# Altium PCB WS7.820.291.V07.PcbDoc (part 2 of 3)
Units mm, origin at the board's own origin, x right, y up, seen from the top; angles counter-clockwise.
Board outline 240.26 x 41.75 mm, 4 copper layers (Top Layer, S2, S3, Bottom Layer); 262 components, 157 nets, 756 pads, 1428 vias.

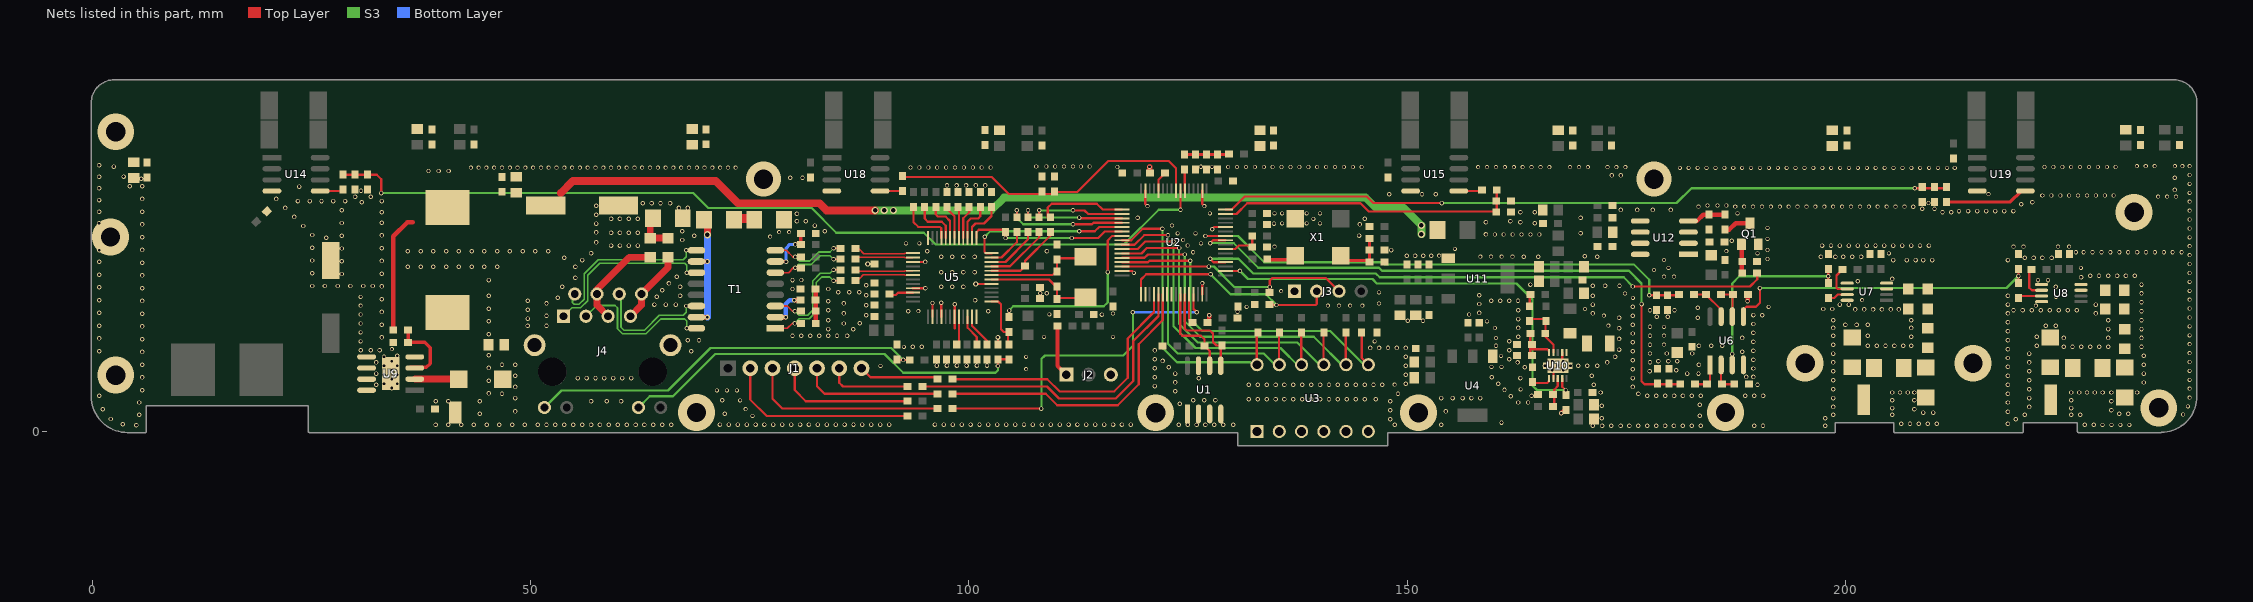
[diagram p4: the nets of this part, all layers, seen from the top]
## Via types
v1: diameter 0.508, hole 0.305, Top Layer to Bottom Layer, tented both sides, 866 vias
v2: diameter 0.457, hole 0.305, Top Layer to Bottom Layer, tented both sides, 327 vias
v3: diameter 0.66, hole 0.406, Top Layer to Bottom Layer, tented both sides, 200 vias
v4: diameter 0.813, hole 0.508, Top Layer to Bottom Layer, tented both sides, 13 vias
v5: diameter 4.2, hole 2.2, Top Layer to Bottom Layer, 10 vias
v6: diameter 0.6, hole 0.3, Top Layer to Bottom Layer, tented both sides, 7 vias
v7: diameter 4/2.2/2.2/3.5 (per signal layer), hole 2.2, Top Layer to Bottom Layer, 2 vias
v8: diameter 0.762, hole 0.508, Top Layer to Bottom Layer, tented both sides, 1 vias
v9: diameter 0.508, hole 0.3, Top Layer to Bottom Layer, tented both sides, 1 vias
v10: diameter 4.191, hole 2.2, Top Layer to Bottom Layer, 1 vias

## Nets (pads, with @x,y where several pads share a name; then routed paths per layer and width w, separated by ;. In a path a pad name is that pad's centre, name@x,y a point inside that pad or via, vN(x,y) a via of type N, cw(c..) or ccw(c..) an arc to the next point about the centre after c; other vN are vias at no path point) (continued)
GND: C1.1 C2.1 C3.1 C4.1 C5.1 C6.1 C7.1 C8.1 C9.1 C10.1 C11.2 C12.2 C13.1 C14.1 C15.1 C16.1 C17.1 C18.1 C19.1 C20.1 C21.1 C22.2 C23.2 C24.1 C25.1 C26.1 C27.1 C28.1 C29.1 C30.1 C31.1 C32.1 C33.1 C34.1 C35.1 C36.1 C37.1 C38.1 C39.1 C40.1 C41.1 C42.1 C43.2 C44.2 C45.2 C46.2 C47.2 C51.2 C52.1 C53.1 C54.1 C55.2 C56.2 C60.1 C61.1 C62.1 C63.1 C64.2 C65.1 C66.1 C67.1 C68.1 C69.1 C70.1 C71.1 C72.2 C73.1 C74.2 C75.2 C76.1 C77.1 C78.1 C79.1 C80.1 C81.1 C82.1 C83.1 C84.2 C85.2 C87.1 C88.1 C89.1 C90.1 C91.1 C92.1 C93.1 C94.1 C95.1 C96.1 C97.1 C98.1 C99.1 C100.1 C101.1 C102.1 C103.1 C104.1 C105.1 C106.1 C107.1 C108.2 C109.2 C110.2 C111.2 C112.1 C113.1 D1.1 FB9.1 FB9.2 FC1.1 J2.3 J3.1 J4.13 J4.14 L3.1 L6.1 L11.1 L12.1 L13.1 Q1.2 R4.2 R8.1 R10.1 R15.1 R52.1 R55.1 R56.1 R57.1 R58.1 R59.1 R60.1 R64.1 R65.1 R66.1 R67.1 R72.1 R73.1 R74.1 R75.1 R82.2 R86.1 R123.1 U1.1 U1.2 U1.3 U1.4 U1.7 U2.12 U2.18 U2.31 U2.47 U2.63 U3.1 U3.3 U3.5 U3.7 U3.9 U3.11 U4.1 U5.3 U5.9 U5.14 U5.16 U5.19 U5.29 U5.48 U6.4 U7.4 U7.5 U7.8 U8.4 U8.5 U8.8 U9.4 U9.5 U9.6 U9.7 U9.8 U9.9 U10.2 U10.7 U10.11 U11.1 U14.4 U15.4 U18.4 U19.4 X1.2 | length 26.8
  Top Layer w0.254: v6(88.464,19.113) C31.1@89.24,19.113 ; U5.9@93.616,16.339 v1(95.051,16.339) ; U5.3@93.616,19.339 v1(95.047,19.339) ; v9(95.86,14.656) 95.866,14.649 U5.14@95.866,13.089 ; v1(96.846,14.668) 96.866,14.648 U5.16@96.866,13.089 ; U5.19@98.366,13.089 98.366,11.743 98.4,11.776 v1(98.4,14.524) ; v6(100.783,16.827) 100.795,16.839 U5.29@102.616,16.839 ; C39.1@103.323,9.93 v6(103.323,10.731) ; U2.47@117.489,18.315 118.626,18.315 v2(118.839,18.102) ; U2.31@120.144,27.463 120.144,26.492 120.144,25.957 v2(120.396,25.705) ; U2.63@126.637,15.66 126.637,16.833 v2@126.644,16.84 ; v2@126.644,16.815 v2(126.644,16.916) ; U2.18@126.644,27.463 126.644,25.985 126.924,25.705 v2(126.873,25.705) ; v1(127.762,23.063) 128.013,23.314 U2.12@129.292,23.314 ; U10.2@166.708,6.018 U10.11@166.708,6.923 ; v1(167.598,2.067) R4.2@167.763,2.067 ; U10.11@167.708,8.113 U10.7@167.708,9.018 ; v1(188.849,14.868) v1@188.857,14.927
  Top Layer w0.508: R10.1@127.215,12.446 127.406,12.637 127.406,12.996 127.432,13.021 v1(127.432,13.25) ; v1(167.598,2.067) 167.983,2.452 R4.2@168.148,2.452 ; v1@188.857,14.927 R75.1@188.857,15.616
  Top Layer w0.635: v2(120.625,30.201) 120.625,29.528 R15.1@120.689,29.464
  other v1: 171.203,0.66 172.257,0.66 173.31,0.66 174.364,0.66 175.38,0.66 176.396,0.66 177.412,0.66 178.427,0.66 179.443,0.66 180.459,0.66 181.475,0.66 182.491,0.66 183.507,0.66 189.603,0.66 190.619,0.66 197.731,0.66 5.029,0.711 39.16,0.762 40.615,0.762 42.07,0.762 43.525,0.762 44.98,0.762 46.435,0.762 47.89,0.762 49.345,0.762 50.8,0.762 51.816,0.762 52.832,0.762 53.848,0.762 54.864,0.762 55.88,0.762 56.896,0.762 57.912,0.762 58.928,0.762 59.944,0.762 60.96,0.762 61.976,0.762 62.992,0.762 64.008,0.762 65.024,0.762 66.04,0.762 123.952,0.762 124.968,0.762 125.984,0.762 127,0.762 128.016,0.762 129.032,0.762 130.175,0.762 148.59,0.762 153.924,0.762 227.33,0.762 228.346,0.762 71.603,0.787 72.619,0.787 73.635,0.787 74.651,0.787 75.667,0.787 76.683,0.787 77.699,0.787 78.715,0.787 79.731,0.787 80.747,0.787 81.763,0.787 82.779,0.787 83.795,0.787 84.811,0.787 85.827,0.787 86.843,0.787 87.859,0.787 88.875,0.787 89.891,0.787 90.907,0.787 96.139,0.787 97.155,0.787 98.171,0.787 99.187,0.787 100.203,0.787 101.219,0.787 102.235,0.787 103.251,0.787 104.267,0.787 105.283,0.787 106.299,0.787 107.315,0.787 108.331,0.787 109.347,0.787 110.363,0.787 111.379,0.787 112.395,0.787 113.411,0.787 114.427,0.787 115.443,0.787 116.459,0.787 117.475,0.787 118.491,0.787 3.48,0.838 206.375,0.889 207.391,0.889 208.407,0.889 209.423,0.889 210.439,0.889 218.567,0.889 160.782,1.016 148.082,1.397 219.456,1.397 2.108,1.422 172.212,1.524 197.739,1.524 183.388,1.778 5.334,1.905 198.628,1.905 205.359,1.905 220.472,1.905 225.806,1.905 226.822,1.905 44.196,2.032 72.136,2.032 231.267,2.032 232.283,2.032 208.915,2.159 210.058,2.159 218.567,2.261 48.26,2.286 154.432,2.286 148.082,2.413 230.378,2.413 1.194,2.54 207.899,2.54 205.359,2.667 225.806,2.667 198.628,2.794 220.98,2.794 172.212,2.921 183.388,3.048 124.079,3.175 5.334,3.302 162.687,3.302 218.567,3.302 39.174,3.429 40.629,3.429 44.196,3.429 56.896,3.429 58.674,3.429 60.325,3.429 148.082,3.429 230.378,3.429 71.882,3.556 125.603,3.556 126.873,3.556 128.143,3.556 205.359,3.556 207.899,3.556 225.806,3.556 131.953,3.683 132.969,3.683 133.985,3.683 135.001,3.683 136.017,3.683 137.033,3.683 138.049,3.683 139.065,3.683 140.081,3.683 141.097,3.683 142.113,3.683 143.129,3.683 144.145,3.683 145.161,3.683 146.431,3.683 48.26,3.81 153.924,3.81 155.194,3.81 156.337,3.81 157.353,3.81 158.369,3.81 198.628,3.81 220.98,3.81 161.842,4.02 164.211,4.064 177.419,4.064 178.435,4.064 179.451,4.064 180.467,4.064 181.483,4.064 182.499,4.064 183.515,4.064 188.595,4.064 189.611,4.064 190.627,4.064 0.777,4.081 46.736,4.318 148.971,4.318 176.403,4.318 218.567,4.318 45.212,4.34 172.085,4.445 205.359,4.445 206.248,4.445 207.137,4.445 207.899,4.445 225.806,4.445 226.695,4.445 227.584,4.445 228.473,4.445 229.362,4.445 230.378,4.445 233.299,4.445 123.542,4.576 5.703,4.704 161.123,4.739 198.628,4.826 220.98,4.826 34.163,4.953 48.26,5.08 175.768,5.08 121.209,5.182 32.385,5.334 131.953,5.334 132.969,5.334 133.985,5.334 135.001,5.334 136.017,5.334 137.033,5.334 138.049,5.334 139.065,5.334 140.081,5.334 141.097,5.334 142.113,5.334 143.129,5.334 144.145,5.334 145.161,5.334 146.177,5.334 147.193,5.334 171.323,5.334 189.992,5.334 218.567,5.334 33.274,5.461 34.798,5.461 149.86,5.461 160.405,5.457 123.542,5.592 234.061,5.588 45.212,5.795 198.628,5.842 220.98,5.842 34.163,5.969 126.238,6.071 55.372,6.096 56.388,6.096 57.404,6.096 58.42,6.096 59.436,6.096 60.452,6.096 61.468,6.096 162.941,6.096 175.768,6.096 5.703,6.159 159.686,6.176 121.209,6.198 188.722,6.223 189.531,6.223 48.26,6.35 171.069,6.35 218.567,6.35 33.274,6.477 34.798,6.477 149.86,6.477 32.385,6.604 123.542,6.608 181.991,6.604 183.261,6.604 234.061,6.604 177.673,6.858 198.628,6.858 220.98,6.858 34.163,6.985 180.721,6.985 166.573,7.01 167.843,7.01 175.768,7.112 189.531,7.182 121.209,7.214 45.212,7.25 122.823,7.326 163.424,7.341 218.567,7.366 33.274,7.493 34.798,7.493 149.86,7.493 165.735,7.493 168.656,7.493 169.545,7.493 170.561,7.493 171.704,7.493 96.36,7.517 97.503,7.517 98.646,7.517 99.746,7.517 100.932,7.517 102.075,7.517 167.208,7.518 5.703,7.614 46.736,7.62 48.26,7.62 183.312,7.624 234.061,7.62 32.385,7.874 162.611,7.874 172.847,7.874 177.724,7.878 198.628,7.874 220.98,7.874 34.163,8.001 178.689,8.001 179.832,8.001 180.848,8.001 166.573,8.026 167.843,8.026 122.105,8.045 175.768,8.128 189.531,8.198 121.209,8.23 161.671,8.255 218.567,8.382 33.274,8.509 149.86,8.509 173.736,8.509 34.798,8.636 234.061,8.636 45.212,8.705 177.724,8.894 179.629,8.894 182.55,8.894 198.628,8.89 220.98,8.89 5.703,9.069 188.254,9.08 68.326,9.144 175.768,9.144 0.777,9.161 189.531,9.214 121.209,9.246 30.607,9.271 31.75,9.271 32.766,9.271 161.671,9.271 174.193,9.345 218.567,9.398 145.796,9.525 146.812,9.525 147.828,9.525 148.844,9.525 149.86,9.525 93.599,9.652 94.615,9.652 224.917,9.652 225.933,9.652 226.949,9.652 227.965,9.652 228.981,9.652 229.997,9.652 233.807,9.652 183.312,9.783 184.709,9.783 185.979,9.783 202.565,9.779 203.581,9.779 204.597,9.779 205.613,9.779 206.629,9.779 207.518,9.779 221.869,9.779 177.724,9.91 198.628,9.906 175.768,10.16 189.531,10.23 161.671,10.287 67.945,10.414 69.215,10.414 218.567,10.414 5.703,10.524 174.193,10.554 0.777,10.616 188.265,10.672 224.917,10.668 229.997,10.668 233.807,10.668 33.02,10.726 162.687,10.795 207.518,10.795 221.869,10.795 79.883,10.922 80.899,10.922 81.915,10.922 82.931,10.922 83.947,10.922 84.963,10.922 86.11,10.926 177.724,10.926 198.628,10.922 202.565,10.922 45.212,11.107 175.768,11.176 189.531,11.246 218.567,11.43 86.828,11.644 83.947,11.684 229.997,11.684 233.807,11.684 174.193,11.764 162.687,11.811 198.628,11.811 207.518,11.811 177.724,11.942 5.703,11.979 0.777,12.071 49.657,12.065 51.816,12.065 222.885,12.065 224.028,12.065 33.02,12.181 175.768,12.192 200.025,12.192 201.295,12.192 202.565,12.192 189.531,12.262 85.725,12.319 87.547,12.363 218.567,12.446 45.212,12.562 150.089,12.624 151.825,12.624 83.947,12.7 198.628,12.7 207.518,12.7 229.997,12.7 233.807,12.7 162.687,12.827 49.662,12.881 183.185,12.958 174.193,12.973 178.486,13.085 179.756,13.085 51.816,13.208 175.768,13.208 190.551,13.265 88.312,13.271 189.531,13.278 115.189,13.335 5.703,13.435 85.725,13.462 171.196,13.462 218.567,13.462 228.6,13.462 0.777,13.526 158.242,13.525 33.02,13.636 130.658,13.64 93.091,13.716 102.235,13.716 233.807,13.716 83.947,13.843 162.687,13.843 177.724,13.847 180.518,13.847 219.202,13.843 220.234,13.843 221.266,13.843 222.298,13.843 223.329,13.843 224.361,13.843 225.393,13.843 226.425,13.843 49.662,13.897 201.143,13.919 202.159,13.919 203.175,13.919 204.191,13.919 205.207,13.919 206.121,13.919 170.307,13.97 197.485,13.97 198.501,13.97 45.212,14.017 183.185,14.101 175.768,14.224 88.312,14.414 64.135,14.478 65.405,14.478 66.548,14.478 171.196,14.478 199.39,14.478 200.406,14.478 218.567,14.478 228.6,14.478 158.242,14.541 51.816,14.605 85.725,14.605 233.807,14.732 83.947,14.859 5.703,14.89 49.662,14.913 159.617,14.91 160.633,14.91 161.649,14.91 162.665,14.91 0.777,14.981 100.711,14.986 33.02,15.091 53.086,15.24 64.389,15.367 45.212,15.472 67.056,15.494 171.196,15.494 218.567,15.494 88.312,15.557 158.242,15.557 233.807,15.748 108.149,15.769 108.89,15.773 85.09,15.875 86.36,15.875 87.503,15.875 65.024,16.129 79.883,16.256 83.947,16.256 5.703,16.345 0.777,16.436 53.594,16.51 67.056,16.51 96.846,16.508 98.116,16.508 99.386,16.508 224.028,16.51 33.02,16.546 25.083,16.594 26.538,16.594 27.994,16.594 29.449,16.594 30.904,16.594 31.978,16.594 171.196,16.637 172.593,16.637 174.244,16.637 88.312,16.7 164.084,16.764 233.807,16.764 65.786,16.891 201.422,17.145 45.212,17.272 79.883,17.272 221.996,17.272 223.139,17.272 205.359,17.399 55.118,17.526 226.909,17.58 66.675,17.653 227.94,17.78 228.956,17.78 229.997,17.78 231.013,17.78 232.029,17.78 233.045,17.78 5.703,17.8 0.777,17.891 28.448,17.965 33.02,18.001 25.083,18.049 96.846,18.159 98.116,18.159 99.386,18.159 100.656,18.159 35.999,18.796 37.454,18.796 38.909,18.796 40.364,18.796 41.819,18.796 43.274,18.796 44.729,18.796 46.184,18.796 55.118,18.796 5.703,19.255 0.777,19.346 28.448,19.42 33.02,19.456 25.083,19.504 55.88,19.558 205.486,19.558 207.01,19.558 208.026,19.558 208.915,19.558 209.931,19.558 218.567,19.558 53.848,19.812 220.472,19.812 221.488,19.812 222.504,19.812 223.545,19.812 96.846,19.937 98.116,19.937 99.386,19.937 100.656,19.937 163.322,19.939 164.973,19.939 171.704,19.939 197.231,19.939 198.882,19.939 199.771,19.939 200.787,19.939 201.803,19.939 170.282,19.99 149.987,20.066 150.914,20.066 151.841,20.066 152.768,20.066 56.896,20.32 233.299,20.447 108.915,20.549 35.999,20.574 37.454,20.574 38.909,20.574 40.364,20.574 41.819,20.574 43.274,20.574 44.729,20.574 46.184,20.574 47.64,20.574 49.095,20.574 50.55,20.574 52.005,20.574 95.25,20.574 0.777,20.674 148.209,20.701 5.703,20.71 28.448,20.875 33.02,20.911 25.083,20.96 59.182,21.209 60.198,21.209 61.214,21.209 62.23,21.209 197.358,21.209 198.374,21.209 199.39,21.209 200.406,21.209 201.422,21.209 202.438,21.209 203.454,21.209 204.47,21.209 205.486,21.209 206.502,21.209 207.518,21.209 208.534,21.209 209.55,21.209 57.48,21.565 187.071,21.747 67.31,21.844 26.67,22.098 5.703,22.165 28.448,22.33 68.682,22.327 144.526,22.352 33.02,22.367 25.083,22.415 159.004,22.479 169.799,22.606 59.182,22.657 60.198,22.657 61.214,22.657 62.23,22.657 57.48,22.708 67.31,22.86 83.566,22.86 24.055,23.443 82.423,23.495 5.703,23.62 144.589,23.622 57.48,23.724 134.823,23.724 0.762,23.749 164.592,23.749 28.448,23.785 33.02,23.822 159.004,23.876 162.941,23.876 80.391,24.003 81.407,24.003 161.798,24.003 59.182,24.257 60.198,24.257 61.214,24.257 62.23,24.257 145.161,24.257 119.253,24.384 169.799,24.384 23.026,24.472 57.48,24.74 80.391,24.841 33.02,25.019 162.941,25.019 164.592,25.019 211.099,25.019 212.115,25.019 0.762,25.077 5.703,25.075 212.979,25.146 214.015,25.146 215.051,25.146 216.086,25.146 217.122,25.146 218.158,25.146 219.194,25.146 28.448,25.24 174.371,25.273 176.276,25.273 178.054,25.273 180.086,25.273 208.788,25.4 210.185,25.4 21.997,25.501 66.929,25.502 67.945,25.502 207.772,25.654 57.48,25.756 220.091,25.908 62.789,26.035 63.805,26.035 64.821,26.035 65.913,26.035 30.727,26.136 221.361,26.162 23.452,26.289 24.796,26.289 26.14,26.289 27.485,26.289 28.829,26.289 33.02,26.289 0.762,26.405 5.703,26.53 20.968,26.53 29.972,26.797 31.75,26.797 222.504,26.924 147.955,27.051 151.707,27.051 153.289,27.051 30.649,27.479 237.617,27.559 0.762,27.733 23.622,27.94 4.248,27.985 5.703,27.985 97.511,28.067 98.6,28.067 99.689,28.067 100.778,28.067 101.867,28.067 5.576,28.829 79.629,28.956 81.026,28.956 237.617,28.956 0.762,29.061 3.556,29.083 173.355,29.21 174.371,29.21 38.354,29.718 39.497,29.718 40.64,29.718 2.424,30.226 0.762,30.389
  other v2: 229.362,0.762 230.378,0.762 231.394,0.762 232.41,0.762 75.311,1.778 238.557,1.93 74.549,2.54 239.09,2.87 163.83,3.302 73.914,3.556 239.293,3.861 71.247,4.699 72.39,4.699 73.533,4.699 162.966,4.801 239.293,4.877 148.59,5.334 239.293,5.893 239.293,6.909 106.553,7.112 159.639,7.366 160.782,7.366 89.916,7.493 239.293,7.925 106.553,8.509 160.729,8.633 239.293,8.941 34.163,9.398 92.583,9.652 160.147,9.779 179.324,9.906 239.293,9.957 30.607,10.287 146.304,10.287 160.147,10.668 108.585,10.795 116.459,10.795 179.324,10.922 239.293,10.973 30.607,11.303 160.02,11.811 179.324,11.938 239.293,11.989 172.974,12.065 30.607,12.319 159.131,12.573 239.293,13.005 172.466,13.208 30.607,13.335 157.099,13.335 109.195,13.36 116.459,13.462 94.234,13.716 239.293,14.021 131.699,14.224 191.262,14.224 30.607,14.351 140.97,14.351 142.24,14.351 143.51,14.351 144.907,14.351 221.742,14.351 146.812,14.605 201.93,14.986 239.293,15.037 175.768,15.24 30.607,15.367 224.028,15.367 174.879,15.748 146.812,15.875 135.636,16.002 239.293,16.053 239.293,17.069 80.899,17.272 179.324,17.653 180.467,17.653 239.293,18.085 178.181,18.415 179.832,18.669 226.883,18.669 239.293,19.101 179.324,19.558 191.135,19.685 158.369,19.939 159.588,19.939 160.807,19.939 162.027,19.939 153.67,20.066 239.293,20.117 189.992,20.32 204.978,20.32 125.603,20.447 226.314,20.447 227.203,20.447 228.219,20.447 229.235,20.447 230.251,20.447 231.267,20.447 232.283,20.447 234.315,20.447 235.331,20.447 236.347,20.447 237.363,20.447 238.379,20.447 186.436,20.574 191.135,20.701 155.448,20.828 134.874,21.082 219.202,21.082 220.345,21.082 224.282,21.082 225.552,21.082 239.293,21.133 124.968,21.209 92.837,21.463 94.361,21.463 126.492,21.463 124.46,21.844 191.135,21.971 239.293,22.149 77.343,22.225 160.02,22.479 161.036,22.479 162.052,22.479 163.068,22.479 164.084,22.479 165.1,22.479 123.825,22.606 125.857,22.606 78.359,22.733 79.502,22.733 239.293,23.165 191.135,23.241 123.19,23.495 135.763,23.749 138.557,23.749 140.081,23.749 239.293,24.181 139.319,24.257 127.508,24.892 134.874,24.892 135.763,24.892 138.557,24.892 140.081,24.892 187.706,24.892 239.293,25.197 183.261,25.654 187.452,25.654 188.468,25.654 189.484,25.654 190.5,25.654 191.516,25.654 192.532,25.654 193.548,25.654 194.564,25.654 195.58,25.654 196.596,25.654 197.612,25.654 198.628,25.654 199.644,25.654 200.66,25.654 201.676,25.654 202.692,25.654 203.708,25.654 204.724,25.654 205.74,25.654 206.756,25.654 184.277,25.781 185.42,25.781 186.436,25.781 209.499,26.06 239.293,26.213 235.712,26.797 236.728,26.797 237.744,26.797 223.52,26.924 224.536,26.924 225.552,26.924 226.568,26.924 227.584,26.924 228.6,26.924 229.616,26.924 230.632,26.924 216.35,27.076 239.293,27.229 239.293,28.245 239.293,29.261 181.127,30.074 182.143,30.074 183.159,30.074 184.175,30.074 185.191,30.074 186.207,30.074 187.223,30.074 188.239,30.074 189.255,30.074 190.271,30.074 191.287,30.074 192.303,30.074 193.319,30.074 194.335,30.074 195.351,30.074 196.367,30.074 197.383,30.074 198.399,30.074 199.415,30.074 200.431,30.074 201.447,30.074 202.463,30.074 203.479,30.074 204.495,30.074 205.511,30.074 206.527,30.074 207.543,30.074 208.559,30.074 209.575,30.074 210.591,30.074 211.607,30.074 212.496,30.074 43.18,30.099 44.069,30.099 44.958,30.099 45.847,30.099 46.736,30.099 47.625,30.099 48.514,30.099 49.403,30.099 50.292,30.099 51.181,30.099 52.07,30.099 52.959,30.099 53.848,30.099 54.737,30.099 55.626,30.099 56.515,30.099 57.404,30.099 58.293,30.099 59.182,30.099 60.071,30.099 60.96,30.099 61.849,30.099 62.738,30.099 63.627,30.099 64.516,30.099 65.405,30.099 66.294,30.099 67.183,30.099 68.072,30.099 68.961,30.099 69.85,30.099 70.739,30.099 71.628,30.099 72.517,30.099 73.406,30.099 93.345,30.124 94.361,30.124 95.377,30.124 96.393,30.124 97.409,30.124 98.425,30.124 99.441,30.124 100.457,30.124 101.473,30.124 102.489,30.124 158.115,30.15 159.131,30.15 160.147,30.15 161.163,30.15 162.179,30.15 163.195,30.15 164.211,30.15 165.227,30.15 166.243,30.15 168.605,30.15 169.621,30.15 170.637,30.15 172.872,30.15 173.888,30.15 174.904,30.15 116.942,30.175 129.591,30.175 130.607,30.175 131.623,30.175 132.639,30.175 133.655,30.175 134.671,30.175 135.687,30.175 136.703,30.175 137.719,30.175 138.735,30.175 139.751,30.175 140.767,30.175 141.783,30.175 142.799,30.175 143.815,30.175 144.831,30.175 222.733,30.175 223.749,30.175 224.765,30.175 225.781,30.175 226.797,30.175 227.813,30.175 228.829,30.175 229.845,30.175 230.861,30.175 126.471,30.203 127.741,30.201 107.696,30.226 108.839,30.226 109.855,30.226 110.871,30.226 111.887,30.226 112.776,30.226 113.792,30.226 233.274,30.277 234.29,30.277 235.306,30.277 237.617,30.277 238.455,30.277 239.293,30.277
  other v5: 121.336,2.134 151.308,2.134 68.936,2.159 186.334,2.159 235.763,2.691 2.667,6.426 195.428,7.772 214.579,7.772 2.057,22.2 232.963,25.004
  other v7: 76.581,28.793 178.181,28.793
  other v10: 2.667,34.188
GND11: C111.1 L13.2
GND12: C110.1 L12.2
GND13: C109.1 L6.2
GND14: C108.1 L3.2
I_SENSOR1: C92.2 C93.2 R93.2 U2.23 | length 103.6
  Top Layer w0.254: R93.2@28.575,29.298 C92.2@31.369,29.298 32.449,29.298 32.969,28.778 v1(32.969,27.203) ; v1@124.144,25.31 U2.23@124.144,27.463
  S3 w0.254: v1(32.969,27.203) 68.555,27.203 70.256,25.502 82.067,25.502 84.887,22.682 94.869,22.682 96.215,21.336 117.704,21.336 121.666,25.298 v1(124.155,25.298)
I_SENSOR2: C103.2 C104.2 R100.2 U2.24 | length 36.5
  Top Layer w0.254: R100.2@92.408,29.047 102.601,29.047 104.546,27.102 109.576,27.102 109.804,27.33 112.37,27.33 115.9,30.861 122.809,30.861 123.644,30.026 U2.24@123.644,27.463
I_SENSOR3: C94.2 C95.2 R94.2 U2.15 | length 34.3
  Top Layer w0.254: U2.15@129.292,24.814 130.555,24.814 131.775,26.035 144.704,26.035 145.644,25.095 160.235,25.095 R94.2@160.235,27.559
I_SENSOR4: C105.2 C106.2 R101.2 U2.16 | length 84.2
  Top Layer w0.254: U2.16@129.292,25.314 130.013,25.314 131.496,26.797 145.415,26.797 146.152,26.06 v1(153.949,26.06) ; v1(207.924,27.762) 211.316,27.762 R101.2@211.582,28.028
  S3 w0.254: v1@154.051,26.162 v1(153.949,26.06) 180.746,26.06 182.448,27.762 v1(207.924,27.762)
IO1: R132.1 U2.45 U3.12 | length 41.7
  Top Layer w0.254: U2.45@117.489,19.315 120.448,19.315 120.615,19.482 v1(125.269,19.482) ; R132.1@144.827,11.272 144.827,8.381 U3.12@145.589,7.619 U3.12@145.589,7.119
  S3 w0.254: v1(125.269,19.482) 125.269,12.831 126.644,11.455 141.253,11.455 U3.12@145.589,7.119
IO2: R127.1 U2.44 U3.10 | length 39.7
  Top Layer w0.254: U2.44@117.489,19.814 120.059,19.814 120.437,20.193 v1@124.583,20.193 ; v1@124.532,20.142 v1@124.583,20.193 ; U3.10@143.02,7.163 R127.1@143.02,11.012 ; v1@124.583,20.193 124.634,20.244 v1(124.634,20.193) v1@124.583,20.193
  S3 w0.254: v1@124.634,20.244 v1(124.634,20.193) 124.634,12.576 126.415,10.795 139.373,10.795 U3.10@143.049,7.119
IO3: R119.1 U2.43 U3.8 | length 38.4
  Top Layer w0.254: U2.43@117.489,20.314 119.695,20.314 120.31,20.93 v1@123.872,20.93 ; v1@123.847,20.904 v1@123.872,20.93 ; U3.8@140.48,7.163 R119.1@140.48,11.012 ; v1@123.872,20.93 123.999,21.057 v1(123.999,20.93) v1@123.872,20.93
  S3 w0.254: v1@123.999,21.057 v1(123.999,20.93) 123.999,12.272 126.111,10.16 137.468,10.16 U3.8@140.509,7.119
IO4: R131.1 U2.42 U3.6 | length 36.1
  Top Layer w0.254: U2.42@117.489,20.814 119.281,20.814 120.132,21.666 v1(123.364,21.666) v1@123.364,21.615 ; U3.6@137.94,7.163 R131.1@137.94,11.012
  S3 w0.254: v1(123.364,21.666) 123.364,12.018 125.857,9.525 135.563,9.525 U3.6@137.719,7.369
IO5: R126.1 U2.41 U3.4 | length 35.8
  Top Layer w0.254: U2.41@117.489,21.314 118.917,21.314 120.005,22.403 v1(122.729,22.403) ; U3.4@135.4,7.163 R126.1@135.4,11.012
  S3 w0.254: v1(122.729,22.403) 122.729,10.011 123.85,8.89 133.658,8.89 U3.4@135.429,7.119
IO6: R118.1 U2.40 U3.2 | length 34.4
  Top Layer w0.254: U2.40@117.489,21.814 118.528,21.814 119.853,23.139 v1(122.094,23.139) ; U3.2@132.86,7.163 R118.1@132.86,11.012
  S3 w0.254: v1(122.094,23.139) 122.094,9.554 123.749,7.899 132.109,7.899 U3.2@132.889,7.119
JTCK: J3.2 R8.2 U2.49 | length 28.1
  Top Layer w0.254: U2.49@119.637,15.66 119.637,17.326 120.244,17.932 v1(127.584,17.932) ; R8.2@134.327,14.478 134.378,14.427 v1(135.103,14.427) 136.957,14.427 ; 139.294,14.427 136.957,14.427 ; J3.2@139.7,16.002 139.7,14.58 139.548,14.427 136.957,14.427
  S3 w0.254: v1(127.584,17.932) 129.87,15.646 133.883,15.646 v1(135.103,14.427)
JTDI: U2.50
JTDO: U2.55
JTMS: J3.3 R6.1 U2.46 | length 27.9
  Top Layer w0.254: U2.46@117.489,18.815 v1(127.381,18.815) ; R6.1@134.327,15.875 134.341,15.889 v1(134.341,16.485) 134.341,17.196 134.645,17.501 140.741,17.501 J3.3@142.24,16.002
  S3 w0.254: v1(127.381,18.815) 127.972,18.815 130.302,16.485 v1(134.341,16.485) v1@134.341,16.612
LINKLED: R50.2 R77.2 U5.25 | length 6.7
  Top Layer w0.254: U5.25@102.616,14.839 103.33,14.839 103.666,14.502 103.666,11.675 103.999,11.342 R77.2@104.593,11.342 ; R77.2@104.466,11.278 104.466,9.93 R50.2@104.67,10.133
M_SCL: R2.1 U1.6 U2.58 | length 10.9
  Top Layer w0.254: U2.58@124.137,15.66 124.137,11.143 124.358,10.922 126.467,10.922 126.881,10.508 R2.1@126.881,9.745 ; R2.1@126.931,9.745 126.931,9.721 127.483,9.169 U1.6@127.483,7.373
M_SDA: R3.1 U1.5 U2.59 | length 11.9
  Top Layer w0.254: U2.59@124.637,15.66 124.637,11.736 124.841,11.532 126.771,11.532 127.508,11.532 127.864,11.176 127.864,10.211 128.256,9.818 R3.1@128.778,9.818 ; R3.1@128.712,9.757 R3.1@128.753,9.716 ; U1.5@128.753,7.373 R3.1@128.753,9.716 ; R3.1@128.778,9.691 R3.1@128.753,9.716
NetC10_2: C10.2 C11.1 FB2.1 X1.4 | length 6.2
  Top Layer w0.381: X1.4@142.427,20.049 142.963,19.513 C10.2@145.716,19.513 ; C10.2@145.716,19.335 C11.1@145.716,20.677 145.716,22.019 FB2.1@145.73,22.032
NetC18_2: C18.2 FB8.1 U12.5 U12.6 U12.7 U12.8
NetC33_2: C33.2 R33.1 R35.1 R37.1 | length 3.9
  Top Layer w0.508: C33.2@82.511,16.256 82.536,16.231 R35.1@82.536,13.722 R37.1@82.536,12.325
NetC35_2: C35.2 R47.2 U5.30 X2.2 | length 13.3
  Top Layer w0.254: U5.30@102.616,17.339 109.151,17.339 110.054,16.435 110.054,15.232 113.557,15.232 113.64,15.314 X2.2@114.271,15.314
NetC36_2: C36.2 J4.9 R45.1 | length 45.8
  Top Layer w0.254: C36.2@91.821,8.23 91.894,8.156 v1(92.507,8.156) R45.1@93.257,8.156
  S3 w0.254: J4.9@51.583,2.734 53.522,4.674 65.684,4.674 70.536,9.525 91.138,9.525 v1(92.507,8.156)
NetC37_2: C37.2 R47.1 U5.31 X2.1 | length 12.4
  Top Layer w0.254: U5.31@102.616,17.839 109.531,17.839 110.054,18.362 110.054,19.755 113.121,19.755 X2.1@113.306,19.939
NetC38_2: C38.2 U5.20 | length 3.3
  Top Layer w0.254: C38.2@98.624,9.93 98.866,10.172 U5.20@98.866,13.089
NetC39_2: C39.2 J4.11 R50.1 | length 46.9
  Top Layer w0.254: v1(103.327,7.468) 103.323,7.471 C39.2@103.323,8.23 R50.1@104.466,8.23
  S3 w0.254: J4.11@62.303,2.734 63.582,4.013 66.243,4.013 71.069,8.839 90.373,8.839 92.507,6.706 103.048,6.706 103.327,6.985 v1(103.327,7.468)
NetC40_2: C40.2 U5.22 | length 3.6
  Top Layer w0.254: U5.22@99.866,13.089 99.866,11.825 100.91,10.781 C40.2@100.91,9.93
NetC41_2: C41.2 R46.1 R48.1 | length 4.4
  Top Layer w0.762: C41.2@63.959,24.308 63.652,24.001 R46.1@63.652,22.067 R48.1@65.684,22.067
NetC42_2: C42.2 R51.1 | length 2.3
  Top Layer w1.016: R51.1@73.197,24.308 C42.2@75.512,24.308
NetC48_1: C48.1 U7.6 | length 3.6
  Top Layer w0.254: C48.1@199.683,18.457 199.009,17.783 199.009,16.383 199.125,16.267 U7.6@200.227,16.267
NetC49_1: C49.1 R63.2 R65.2
NetC49_2: C49.2 C50.1 R66.2
NetC50_2: C50.2 U7.3
NetC52_2: C52.2 R61.2 U6.3 | length 25.6
  Top Layer w0.254: U6.3@187.111,7.346 v1(187.111,8.829) ; R61.2@198.069,16.928 v1(198.069,17.704) C52.2@198.069,18.53
  S3 w0.254: v1(187.111,8.829) 187.111,16.891 187.923,17.704 191.643,17.704 ; 188.468,17.704 191.643,17.704 ; v1(198.069,17.704) 191.643,17.704
NetC57_1: C57.1 U8.6 | length 3.7
  Top Layer w0.254: C57.1@221.273,18.457 221.005,18.189 221.005,17.792 221.005,17.602 221.005,16.408 221.306,16.108 U8.6@222.406,16.108
NetC58_1: C58.1 R71.2 R73.2
NetC58_2: C58.2 C59.1 R74.2
NetC59_2: C59.2 U8.3
NetC61_2: C61.2 R69.2 U6.5 | length 36.6
  Top Layer w0.254: U6.5@188.381,12.846 188.381,13.883 188.722,14.224 189.81,14.224 190.271,14.686 v1(190.271,16.362) ; R69.2@219.761,16.928 v1(219.761,17.729) C61.2@219.761,18.53
  S3 w0.254: v1(190.271,16.362) 218.394,16.362 v1(219.761,17.729)
NetC68_2: C68.2 C72.1 C73.2 FB11.1 L4.2 R80.2 | length 118.8
  Top Layer w0.5: R80.2@34.329,11.557 34.329,22.264 35.941,23.876 36.576,23.876
  Top Layer w0.889: 53.447,27.197 54.825,28.575 71.12,28.575 73.66,26.035 82.956,26.035 83.769,25.222 v4(89.306,25.222)
  S3 w0.889: v4(151.638,22.502) v4(151.638,23.518) 149.629,25.527 146.431,25.527 145.275,26.683 104.026,26.683 102.565,25.222 v4(91.389,25.222) ; v4(91.389,25.222) v4(89.306,25.222) v4(90.348,25.222) v4(91.389,25.222)
NetC75_1: C75.1 L5.2 R85.2 U12.1 U12.2 U12.3
NetC81_2: C81.2 C82.2 R83.2 R84.2 R86.2 | length 5.1
  Top Layer w0.381: R84.2@124.587,31.593 C81.2@127.115,31.593 129.633,31.593 R83.2@129.706,31.666
NetC84_1: C84.1 C85.1 R22.2 U10.10 | length 4.9
  Top Layer w0.254: C84.1@163.994,8.661 164.072,8.739 R22.2@164.072,11.201 ; 164.072,9.373 166.014,9.373 166.208,9.179 U10.10@166.208,9.018
NetC86_1: C86.1 R22.1 R25.2 U10.9 | length 5.7
  Top Layer w0.254: C86.1@163.999,12.841 R25.2@165.845,12.841 ; R25.2@165.811,12.51 165.811,10.795 166.708,9.898 U10.9@166.708,9.018
NetC86_2: C86.2 R27.2 | length 1.3
  Top Layer w0.254: C86.2@163.999,14.541 R27.2@163.999,15.827
NetC90_2: C90.2 R23.2 U10.3 | length 3.4
  Top Layer w0.254: R23.2@166.915,2.87 166.793,2.992 166.793,4.766 167.208,5.182 U10.3@167.208,6.018
NetC97_2: C97.2 U10.1 | length 2.4
  Top Layer w0.254: C97.2@164.248,5.74 164.451,5.537 165.989,5.537 166.208,5.756 U10.1@166.208,6.018
NetD1_2: D1.2 L4.1 U9.2 | length 5
  Top Layer w0.8: U9.2@36.786,5.969 D1.2@41.823,5.969
NetD2_2: D2.2 L11.2 U10.6
NetJ1_2: J1.2 R32.1 | length 22.3
  Top Layer w0.254: J1.2@75.057,7.208 75.057,3.632 76.911,1.778 R32.1@93.003,1.778
NetJ1_3: J1.3 R31.1 | length 22.8
  Top Layer w0.254: J1.3@77.597,7.208 77.597,3.734 78.715,2.616 R31.1@96.432,2.616
NetJ1_4: J1.4 R30.1 | length 15.9
  Top Layer w0.254: J1.4@80.137,7.208 80.137,4.724 81.407,3.454 R30.1@93.003,3.454
NetJ1_5: J1.5 R29.1 | length 16.2
  Top Layer w0.254: J1.5@82.677,7.208 82.677,5.156 83.541,4.293 R29.1@96.432,4.293
NetJ1_6: J1.6 R28.1 | length 9.6
  Top Layer w0.254: J1.6@85.217,7.208 85.217,5.563 85.649,5.131 R28.1@93.003,5.131
NetJ1_7: J1.7 R26.1 | length 9.2
  Top Layer w0.254: J1.7@87.757,7.208 88.793,6.172 96.229,6.172 R26.1@96.432,5.969
NetJ2_1: J2.1 L1.1 | length 6
  Top Layer w0.508: L1.1@110.123,12.014 110.123,7.479 J2.1@111.125,6.477
NetJ4_4: J4.4 J4.5 R46.2 | length 11.2
  Top Layer w0.762: J4.5@58.848,13.144 57.578,14.414 J4.4@57.578,15.684 57.578,16.201 61.243,19.867 R46.2@63.652,19.867
NetJ4_7: J4.7 J4.8 R48.2 | length 8.5
  Top Layer w0.762: J4.7@61.388,13.144 62.658,14.414 J4.8@62.658,15.684 65.684,18.711 R48.2@65.684,19.867
NetQ1_1: Q1.1 R88.2 R123.2 | length 3.3
  Top Layer w0.508: Q1.1@188.178,21.372 188.178,18.128 R88.2@188.249,18.056
NetQ1_3: Q1.3 R87.1 | length 3.1
  Top Layer w0.508: R87.1@186.294,23.038 186.768,23.038 187.503,23.772 Q1.3@189.128,23.772
NetR9_1: R9.1 X1.3 | length 3
  Top Layer w0.381: R9.1@134.372,19.604 136.783,19.604 X1.3@137.227,20.049
NetR10_2: R10.2 U2.60 | length 3.4
  Top Layer w0.254: U2.60@125.137,15.66 125.137,13.329 125.137,12.824 R10.2@125.515,12.446
NetR15_2: R15.2 U2.28 | length 2.3
  Top Layer w0.254: U2.28@121.644,27.463 121.644,28.719 R15.2@122.389,29.464
NetR16_1: R16.1 U2.36 | length 14
  Top Layer w0.254: R16.1@105.486,24.447 v1(105.486,25.222) ; v1(111.887,23.647) 114.071,23.647 114.238,23.814 U2.36@117.489,23.814
  S3 w0.254: v1(105.486,25.222) 105.486,24.359 106.197,23.647 v1(111.887,23.647)
NetR17_1: R17.1 U2.35 | length 12.2
  Top Layer w0.254: R17.1@106.756,24.447 v1(106.756,25.222) ; v1@112.598,24.314 U2.35@117.489,24.314
  S3 w0.254: v1(106.756,25.222) 106.756,24.638 106.985,24.409 v1(112.598,24.409)
NetR18_1: R18.1 U2.34 | length 10.5
  Top Layer w0.254: R18.1@108.026,24.447 v1(108.026,25.222) v1@108.026,25.349 ; v1(111.887,25.222) 113.208,25.222 113.616,24.814 U2.34@117.489,24.814
  S3 w0.254: v1(108.026,25.222) v1(111.887,25.222)
NetR19_1: R19.1 U2.33 | length 10
  Top Layer w0.254: R19.1@109.017,24.447 109.017,25.552 109.449,25.984 114.605,25.984 115.275,25.314 U2.33@117.489,25.314
NetR49_1: R49.1 U5.45 | length 6.3
  Top Layer w0.254: R49.1@93.697,25.629 93.697,23.88 94.234,23.343 96.317,23.343 96.698,23.343 96.866,23.174 U5.45@96.866,22.089
NetR51_2: R51.2 T1.10 T1.15 | length 13.9
  Top Layer w0.508: T1.15@68.928,13.042 v6(70.176,13.042) ; T1.10@68.928,19.392 v6(70.176,19.392)
  Top Layer w0.762: R51.2@69.797,24.308 70.176,23.929 v4(70.176,22.45)
  Bottom Layer w0.762: v6(70.176,13.042) v6(70.176,19.392) v4(70.176,22.45) v4@70.18,22.454
NetR52_2: R52.2 U5.10 | length 2.4
  Top Layer w0.254: R52.2@91.357,15.557 91.63,15.557 91.912,15.839 U5.10@93.616,15.839
NetR53_1: R53.1 U5.44 | length 5.9
  Top Layer w0.254: R53.1@94.967,25.201 R53.1@94.967,25.629 94.967,24.286 95.326,23.927 96.926,23.927 97.366,23.487 U5.44@97.366,22.089
NetR54_1: R54.1 U5.43 | length 5.3
  Top Layer w0.254: 96.237,25.099 R54.1@96.237,25.629 96.237,24.769 96.495,24.511 97.358,24.511 97.866,24.003 U5.43@97.866,22.089
NetR55_2: R55.2 U5.23 | length 3.9
  Top Layer w0.254: U5.23@100.366,13.089 100.366,12.062 102.053,10.375 R55.2@102.053,9.93
NetR56_2: R56.2 U5.38 | length 5
  Top Layer w0.254: U5.38@100.366,22.089 100.366,23.328 100.762,23.724 101.727,23.724 102.587,24.583 R56.2@102.587,25.629
NetR57_2: R57.2 U5.39 | length 4.7
  Top Layer w0.254: U5.39@99.866,22.089 99.866,23.946 100.228,24.308 101.067,24.308 101.317,24.558 R57.2@101.317,25.629 R57.2@101.342,25.603
NetR58_2: R58.2 U5.40 | length 3.8
  Top Layer w0.254: U5.40@99.366,22.089 99.366,24.335 100.047,25.015 R58.2@100.047,25.629
NetR59_2: R59.2 U5.41 | length 4.1
  Top Layer w0.254: R59.2@98.511,25.363 R59.2@98.777,25.629 ; U5.41@98.866,22.089 R59.2@98.866,25.845
NetR60_2: R60.2 U5.42 | length 3.9
  Top Layer w0.254: R60.2@97.507,25.629 97.507,25.404 98.366,24.544 U5.42@98.366,22.089
NetR61_1: R61.1 U7.7 | length 2.8
  Top Layer w0.254: R61.1@198.069,15.228 198.743,15.228 199.132,15.617 U7.7@200.227,15.617 U7.7@200.735,15.617
NetR62_1: R62.1 R68.2 U6.1 | length 5.1
  Top Layer w0.254: R62.1@182.881,5.388 R68.2@184.229,5.388 ; R68.2@184.571,5.222 U6.1@184.571,7.346 ; R68.2@184.571,5.654 184.571,6.655 184.571,6.009
NetR67_2: R67.2 R68.1 U6.2 | length 3.5
  Top Layer w0.254: U6.2@185.841,7.346 185.841,5.388 R67.2@187.335,5.388
NetR69_1: R69.1 U8.7 | length 2.2
  Top Layer w0.254: 220.211,15.458 U8.7@222.406,15.458
NetR70_1: R70.1 R76.2 U6.7 | length 4.8
  Top Layer w0.254: R70.1@182.754,15.616 184.102,15.616 185.841,13.877 U6.7@185.841,12.846
NetR75_2: R75.2 R76.1 U6.6 | length 4.4
  Top Layer w0.254: R76.1@185.802,15.616 R75.2@187.15,15.616 ; U6.6@187.111,12.846 187.15,12.885 R75.2@187.15,15.845
NetR77_1: R77.1 U2.39 | length 21.4
  Top Layer w0.254: R77.1@104.593,13.042 104.593,13.814 104.597,13.818 v1(104.597,13.792) ; v1(115.849,18.186) 115.849,21.793 116.371,22.314 U2.39@117.489,22.314
  S3 w0.254: v1(104.597,13.792) 105.08,14.275 115.411,14.275 115.849,14.713 v1(115.849,18.186)
NetR80_1: R80.1 R82.1 U9.3 | length 8.3
  Top Layer w0.381: R80.1@36.029,11.43 R82.1@36.029,10.16 37.922,10.16 38.532,9.55 38.532,7.747 38.102,7.317 U9.3@36.271,7.317
NetR85_1: R85.1 R87.2 U12.4 | length 4.5
  Top Layer w0.508: U12.4@182.114,24.015 183.089,24.015 183.812,24.738 R85.1@184.447,24.738 R87.2@186.294,24.738
NetR93_1: R93.1 U14.5 | length 2.4
  Top Layer w0.254: U14.5@25.737,27.432 28.106,27.432
NetR94_1: R94.1 U15.5 | length 2.7
  Top Layer w0.254: U15.5@155.912,27.432 158.535,27.432 R94.1@158.662,27.432
NetR100_1: R100.1 U18.5 | length 2.5
  Top Layer w0.254: U18.5@89.872,27.432 92.392,27.432 R100.1@92.408,27.449
NetR101_1: R101.1 U19.5 | length 9.5
  Top Layer w0.381: R101.1@211.582,26.289 211.684,26.187 218.846,26.187 220.091,27.432 U19.5@220.555,27.432
NJTRST: U2.56
NRST_CPU: C2.2 R1.1 U2.7 | length 4.5
  Top Layer w0.254: U2.7@129.292,20.814 130.415,20.814 130.81,21.209 C2.2@132.344,21.209 ; C2.2@132.344,21.051 R1.1@132.344,22.322
OPD: R63.1 R64.2 SMA1.1
POWER_LED: R26.2 U2.52 | length 32.1
  Top Layer w0.254: R26.2@98.132,5.969 108.941,5.969 110.338,4.572 116.586,4.572 ; 116.638,4.572 116.586,4.572 ; U2.52@121.137,15.66 121.137,13.619 118.135,10.617 118.135,6.121 116.586,4.572
PTT_SW: R88.1 U2.4 | length 67.6
  Top Layer w0.254: v1(127.533,19.71) 127.929,19.315 U2.4@129.292,19.315 ; v1(175.768,16.54) 189.133,16.54 189.949,17.356 R88.1@189.949,18.056
  S3 w0.254: v1(127.533,19.71) 130.785,19.71 132.461,18.034 146.431,18.034 146.876,17.589 160.655,17.589 ; 161.519,17.589 160.655,17.589 ; v1(175.768,16.54) 174.719,17.589 160.655,17.589
RFOUT_LED: R28.2 U2.53 | length 36.5
  Top Layer w0.254: R28.2@94.703,5.131 108.915,5.131 110.287,3.759 116.764,3.759 118.77,5.766 118.77,10.312 121.637,13.179 U2.53@121.637,15.66
RPD: R71.1 R72.2 SMA2.1
RTC: R33.2 T1.2 | length 4.6
  Top Layer w0.508: T1.2@77.928,13.042 v1(79.107,13.042) ; v1(80.067,14.986) R33.2@80.811,14.986 R33.2@80.817,14.992
  Bottom Layer w0.508: v1(79.107,13.042) 79.107,14.541 79.553,14.986 v1(80.067,14.986)
RX1_N: J4.6 T1.14 | length 15.3
  Top Layer w0.191: v1(67.779,14.312) T1.14@68.928,14.312 v1@67.823,14.312
  S3 w0.191: J4.6@60.118,15.684 60.325,15.477 60.325,11.887 60.655,11.557 63.001,11.557 64.69,13.245 67.423,13.245 67.779,13.601 v1(67.779,14.312)
RX1_P: J4.3 T1.16 | length 18.6
  Top Layer w0.191: v1(67.806,11.772) T1.16@68.928,11.772 v1@67.823,11.772
  S3 w0.191: J4.3@56.308,13.144 57.54,14.376 59.639,14.376 59.919,14.097 59.919,11.719 60.487,11.151 63.17,11.151 64.858,12.839 67.578,12.839 67.806,12.61 v1(67.806,11.772)
RX_N: R42.1 U5.5 | length 6.4
  Top Layer w0.191: R42.1@87.308,18.52 87.536,18.292 92.668,18.292 92.715,18.339 U5.5@93.616,18.339
RX_P: R40.1 U5.6 | length 6.5
  Top Layer w0.191: R40.1@87.308,17.462 87.55,17.462 87.974,17.885 92.668,17.885 92.715,17.839 U5.6@93.616,17.839
SPDLED: U5.24
SPI2_MISO: R17.2 U5.34 | length 6
  Top Layer w0.254: U5.34@102.616,19.339 104.175,19.339 106.756,21.92 R17.2@106.756,22.747
SPI2_MOSI: R16.2 U5.35 | length 4.8
  Top Layer w0.254: U5.35@102.616,19.839 103.735,19.839 105.486,21.59 R16.2@105.486,22.747
SPI2_NSS: R19.2 R41.1 U5.32 | length 9.1
  Top Layer w0.254: U5.32@102.616,18.339 105.89,18.339 R41.1@106.41,18.859 106.41,19.441 109.296,22.327 R19.2@109.296,22.747
SPI2_SCK: R18.2 U5.33 | length 7.4
  Top Layer w0.254: U5.33@102.616,18.839 104.691,18.839 108.026,22.174 R18.2@108.026,22.747
START_SOFT: R4.1 U2.2 U10.4 | length 51.7
  Top Layer w0.254: U2.2@129.292,18.315 v1(130.937,18.315) ; U10.4@167.708,6.018 167.708,5.113 v2(168.097,4.724)
  S3 w0.254: v1(130.937,18.315) 131.853,17.399 146.05,17.399 146.558,16.891 162.494,16.891 164.321,15.064 164.321,5.224 164.821,4.724 v2(168.097,4.724)
TCT: C34.2 R38.1 T1.7 | length 5.9
  Top Layer w0.381: T1.7@77.928,19.392 79.135,19.392 v1(79.146,19.38) ; v1(80.213,21.336) 80.219,21.342 R38.1@80.836,21.342 C34.2@80.836,22.612
  Bottom Layer w0.381: v1(79.146,19.38) 79.146,20.93 79.553,21.336 v1(80.213,21.336)
TEMP_LED: R31.2 U2.61 | length 40.6
  Top Layer w0.254: R31.2@98.132,2.616 105.054,2.616 v1(108.28,2.616) ; 125.637,14.368 125.637,14.757 ; U2.61@125.637,15.66 125.637,14.757 ; v1(126.009,13.589) 125.637,13.961 125.637,14.757
  S3 w0.254: v1(108.28,2.616) 108.28,8.255 108.687,8.661 117.627,8.661 118.72,9.754 v1(118.72,13.589)
  Bottom Layer w0.254: v1(118.72,13.589) v1(126.009,13.589)
TX1_N: J4.2 T1.9 | length 20
  Top Layer w0.191: v1(67.779,20.662) T1.9@68.928,20.662
  S3 w0.191: J4.2@55.038,15.684 54.788,15.434 54.788,14.681 54.966,14.503 55.524,14.503 56.109,15.088 56.109,17.999 57.705,19.595 67.423,19.595 67.779,19.951 v1(67.779,20.662)
TX1_P: J4.1 T1.11 | length 20.3
  Top Layer w0.191: v1(67.806,18.122) T1.11@68.928,18.122
  S3 w0.191: J4.1@53.768,13.144 54.721,14.097 55.693,14.097 56.515,14.919 56.515,17.831 57.873,19.189 67.578,19.189 67.806,18.96 v1(67.806,18.122)
TX_N: R44.1 U5.1 | length 6.5
  Top Layer w0.191: R44.1@87.308,20.764 87.55,20.764 88.022,20.292 92.668,20.292 92.715,20.339 U5.1@93.616,20.339
TX_P: R43.1 U5.2 | length 6.7
  Top Layer w0.191: R43.1@86.9,19.885 92.668,19.885 92.715,19.839 U5.2@93.616,19.839
V+: C53.2 C54.2 R62.2 U2.9 | length 69.7
  Top Layer w0.254: v1(127.533,21.488) 127.859,21.814 U2.9@129.292,21.814 ; v1(176.759,14.533) 176.759,5.715 177.086,5.388 R62.2@181.181,5.388
  S3 w0.254: v1(127.533,21.488) 130.219,21.488 133.038,18.669 146.812,18.669 147.155,18.326 160.528,18.326 ; 161.519,18.326 160.528,18.326 ; v1(176.759,14.533) 176.759,16.891 175.324,18.326 160.528,18.326
V-: C62.2 C63.2 R70.2 U2.10 | length 61.2
  Top Layer w0.254: v1(126.999,22.301) 127.012,22.314 U2.10@129.292,22.314 ; v1(177.648,15.543) C62.2@178.475,15.543 C63.2@179.745,15.543 180.98,15.543 R70.2@181.054,15.616
  S3 w0.254: v1(126.999,22.301) 130.722,22.301 133.719,19.304 147.193,19.304 147.435,19.062 160.528,19.062 ; 161.519,19.062 160.528,19.062 ; v1(177.648,15.543) 177.648,17.297 175.883,19.062 160.528,19.062
VGS1: C22.1 L7.2
VGS2: C23.1 L8.2
VGS3: C43.1 L9.2
VGS4: C51.1 L10.2
VOLT_DEC: R84.1 U2.22 | length 2.1
  Top Layer w0.254: U2.22@124.644,27.463 R84.1@124.644,29.537
VSWR_LED: R29.2 U2.54 | length 34.6
  Top Layer w0.254: R29.2@98.132,4.293 108.788,4.293 110.084,2.997 116.992,2.997 119.38,5.385 119.38,5.969 ; 119.38,5.554 119.38,5.969 ; U2.54@122.137,15.66 122.137,12.714 119.38,9.957 119.38,5.969
W5500_INTN: U2.37 U5.36 | length 18.7
  Top Layer w0.254: v1(101.803,22.2) 101.803,20.498 101.962,20.339 U5.36@102.616,20.339 ; v1(112.598,22.835) 114.376,22.835 114.856,23.314 U2.37@117.489,23.314
  S3 w0.254: v1(101.803,22.2) 102.438,22.835 v1(112.598,22.835)
W5500_RSTN: R39.1 U2.38 U5.37 | length 18.2
  Top Layer w0.254: U5.37@100.866,22.089 100.866,22.736 101.143,23.012 R39.1@104.165,23.012 ; v1(104.191,22.073) 104.191,22.098 R39.1@104.191,22.747 ; v1@111.887,22.073 114.783,22.073 115.524,22.814 U2.38@117.489,22.814
  S3 w0.254: v1(104.191,22.073) v1(111.76,22.073)
W5500_RX1_N: R35.2 R42.2 T1.3 | length 12.6
  Top Layer w0.191: T1.3@77.928,14.312 79.287,14.312 79.877,13.722 80.035,13.722 v1(80.162,13.722) R35.2@80.836,13.722 ; v1(84.568,18.435) R42.2@85.354,18.435
  S3 w0.191: v1(80.162,13.722) 80.625,13.259 81.61,13.259 82.194,13.843 82.194,17.161 83.067,18.034 84.167,18.034 v1(84.568,18.435)
W5500_RX1_P: R37.2 R40.2 T1.1 | length 12.7
  Top Layer w0.191: T1.1@77.928,11.772 79.285,11.772 79.838,12.325 v1(80.137,12.325) R37.2@80.836,12.325 ; v1(84.568,17.208) R40.2@85.354,17.208
  S3 w0.191: v1(80.137,12.325) 80.665,12.852 81.779,12.852 82.601,13.675 82.601,16.993 83.236,17.628 84.148,17.628 v1(84.568,17.208)
W5500_TX1_N: R34.1 R44.2 T1.8 | length 9.2
  Top Layer w0.191: T1.8@77.928,20.662 79.185,20.662 79.934,19.914 v1(80.188,19.914) R34.1@80.836,19.914 ; v1(84.568,20.891) R44.2@85.354,20.891
  S3 w0.191: v1(80.188,19.914) 80.651,19.451 81.87,19.451 82.892,20.472 84.158,20.472 v1@84.568,20.883
W5500_TX1_P: R36.1 R43.2 T1.6 | length 9
  Top Layer w0.191: T1.6@77.928,18.122 79.438,18.122 79.985,18.669 R36.1@80.836,18.669 ; v1(84.568,19.663) R43.2@85.354,19.663
  S3 w0.191: v1(80.213,18.694) 80.563,19.044 82.039,19.044 83.06,20.066 84.158,20.066 v1@84.561,19.663
pads on no net: J4.15 J4.16 T1.4 T1.5 T1.12 T1.13 U2.3 U2.6 U2.8 U2.11 U2.14 U2.17 U2.20 U2.25 U2.26 U2.27 U2.29 U2.30 U4.4 U5.7 U5.12 U5.13 U5.18 U5.46 U5.47 U11.4 U14.3 U14.6 U14.7 U15.3 U15.6 U15.7 U18.3 U18.6 U18.7 U19.3 U19.6 U19.7 X1.1

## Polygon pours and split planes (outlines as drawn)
GND on Top Layer "Top Layer-No Net" (solid, remove dead copper, pour order 1000): -1.488,41.709 241.64,41.709 243.088,40.261 243.088,2.898 238.77,-1.42 236.129,-4.062 136.281,-4.062 -0.777,-4.062 -3.216,-1.623 -3.216,39.982 -1.488,41.709
GND on S2 "Top Layer-No Net" (solid, remove dead copper, pour order 1001): -1.524,30.734 241.681,30.734 242.468,29.947 242.468,0.66 239.573,-2.235 -0.076,-2.235 -3.251,0.94 -3.251,29.007 -1.524,30.734
GND on S3 "Top Layer-No Net" (solid, remove dead copper, pour order 1002): -1.524,30.734 241.681,30.734 242.468,29.947 242.468,0.66 239.573,-2.235 -0.076,-2.235 -3.251,0.94 -3.251,29.007 -1.524,30.734
GND on Bottom Layer "Top Layer-No Net" (solid, remove dead copper, pour order 1003): -1.524,30.734 241.681,30.734 242.468,29.947 242.468,0.66 239.573,-2.235 -0.076,-2.235 -3.251,0.94 -3.251,29.007 -1.524,30.734
GND on Bottom Solder "Top Layer-No Net" (solid, remove dead copper): 191.999,-0.127 191.999,13.394 240.86,13.394 241.3,12.954 241.3,1.778 238.633,-0.889 192.786,-0.889 192.532,-1.143 192.532,-0.762 191.77,0
GND on Bottom Solder "Top Layer-No Net" (solid, remove dead copper): 147.689,-1.551 147.689,18.53 148.844,19.685 173.99,19.685 174.371,19.304 174.371,-1.651 173.863,-2.159 173.255,-1.551 147.689,-1.551

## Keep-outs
Keep-Out Layer:
  lines w0.254: -0.005,37.492 cw(c2.503,37.492) 2.503,40 237.508,40 ; 0,4.039 0,35.992 ; 0,29.515 0,37.492 ; 0.008,4 ccw(c4.008,4) 4.008,0 6.026,0 6.026,3.048 24.765,3.048 24.765,0 130.789,0 130.789,-1.5 147.689,-1.5 147.689,0 ; 147.752,0 198.755,0 198.755,1.146 205.664,1.146 205.664,0 220.193,0 220.193,1.146 226.619,1.146 226.619,0 236,0 ; 236,0.013 ccw(c236,4.013) 240,4.013 240,37.503 ccw(c237.508,37.503) 237.508,39.995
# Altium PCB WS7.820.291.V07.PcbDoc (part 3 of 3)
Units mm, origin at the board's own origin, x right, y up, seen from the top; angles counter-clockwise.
Board outline 240.26 x 41.75 mm, 4 copper layers (Top Layer, S2, S3, Bottom Layer); 262 components, 157 nets, 756 pads, 1428 vias.

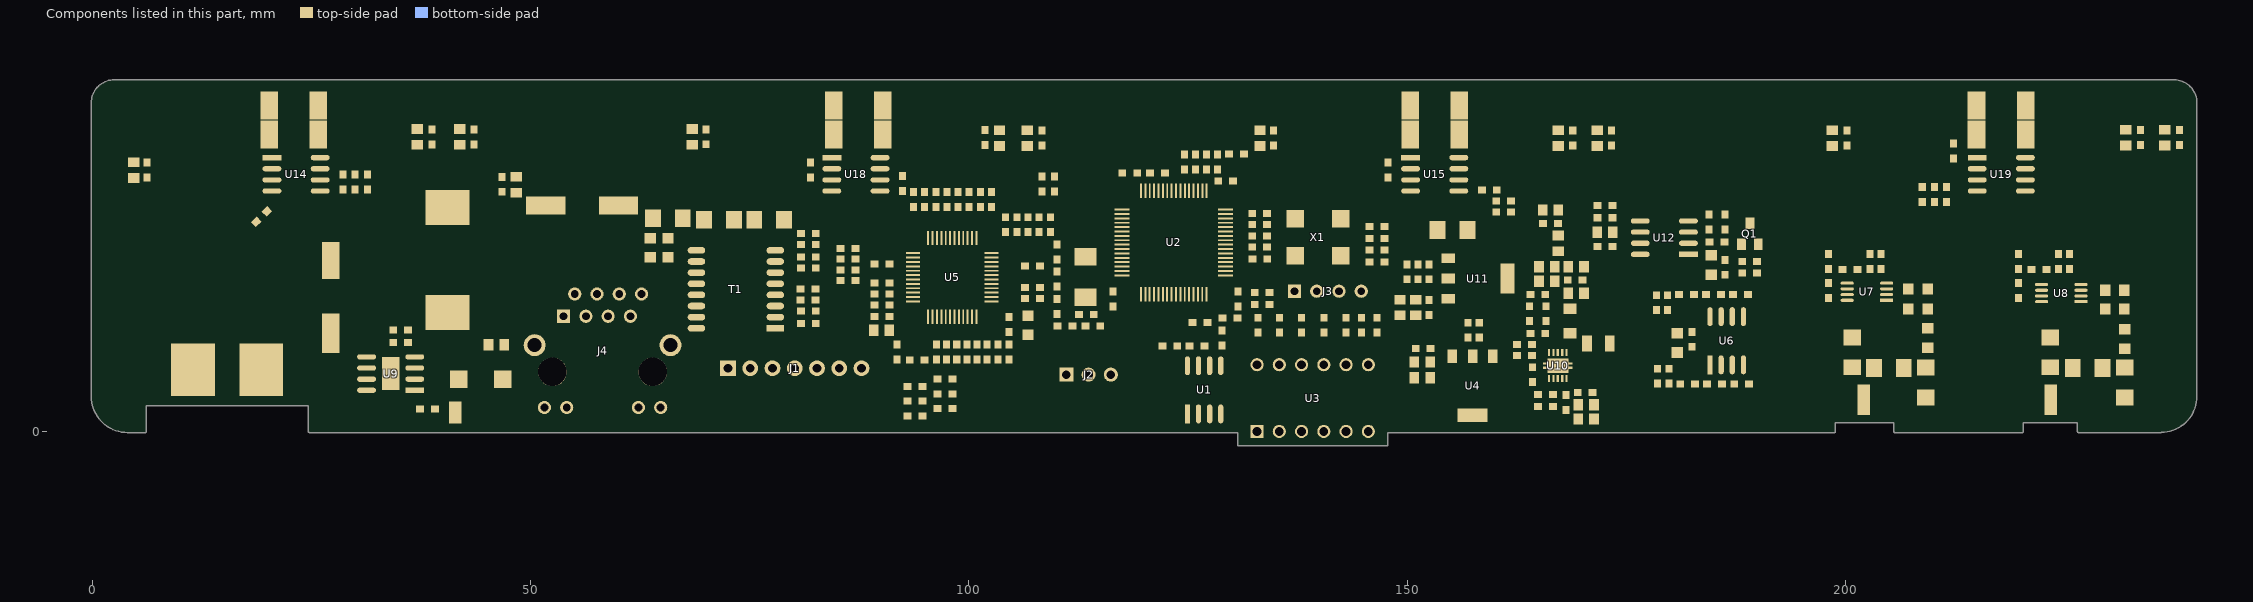
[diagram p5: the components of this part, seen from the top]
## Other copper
Top Layer:
  region net 28VIN: 16.827,30.798 19.296,33.266 18.308,34.254 15.839,31.786
  rectangle net GND: 168.36,30.226 169.418,33.077
  rectangle net GND: 38.185,30.099 39.243,33.204
  rectangle net GND: 43.011,30.353 44.069,33.204
  rectangle net GND: 67.691,30.099 70.612,33.274
  rectangle net GND: 101.304,29.972 102.362,33.128
  rectangle net GND: 107.781,29.972 108.839,33.077
  rectangle net GND: 132.588,28.321 135.255,33.02
  rectangle net GND: 146.558,27.178 148.463,29.445
  rectangle net GND: 144.526,27.94 148.209,29.445
  rectangle net GND: 172.993,23.834 174.066,26.331
  rectangle net GND: 79.248,27.559 82.296,29.464
  rectangle net NetD1_2: 37.592,11.43 43.18,15.875
  rectangle net GND: 38.608,0.388 40.894,3.942
  region net 28VIN: 86.436,32.43 86.436,39.161 79.908,39.161 79.908,32.43
  region net 28VIN: 152.222,32.43 152.222,39.161 145.694,39.161 145.694,32.43
  rectangle net GND: 29.969,4.191 35.052,5.82
  rectangle net GND11: 3.937,30.24 6.803,31.394
  rectangle net GND: 197.739,29.312 200.762,33.02
  rectangle net GND: 206.883,29.362 212.369,30.683
  rectangle net GND: 211.75,28.851 212.776,31.598
  region net GND: 19.955,24.384 21.738,26.167 20.96,26.945 19.177,25.162
  rectangle net -5V_00: 165.329,13.741 167.792,16.027
  rectangle net 28VIN: 147.218,30.277 151.257,33.223
  rectangle net 28VOUT4: 219.298,30.937 221.717,32.581
  rectangle net 28VIN: 213.995,29.642 216.103,33.111
  region net 28VIN: 216.84,32.43 216.84,39.161 210.312,39.161 210.312,32.43
  rectangle net 28VOUT4: 219.298,32.581 225.628,38.855
  rectangle net 28VIN: 10.922,4.005 21.717,21.463
  region net -5V_00: 166.776,14.122 166.776,10.363 167.335,10.363 167.335,14.122
  region net -5V_00: 166.776,10.363 167.094,10.046 167.323,10.274 167.005,10.592
  region net -5V_00: 166.395,21.082 166.395,13.741 168.859,13.741 168.859,21.082
  region net NetD2_2: 168.063,12.09 168.063,8.636 171.45,8.636 171.45,12.09
  region net +5V: 168.252,6.411 168.252,5.639 168.976,5.639 168.976,6.411
  region net GND: 165.329,8.331 165.329,6.706 168.91,6.706 168.91,8.331
  region net GND: 168.91,8.026 168.91,6.706 173.736,6.706 173.736,8.026
  region net RPD: 223.939,4.63 223.939,6.807 222.939,6.807 222.939,4.63
  region net NetC58_1: 232.394,6.477 232.394,9.906 231.394,9.906 231.394,6.477
  rectangle net NetC75_1: 181.077,19.513 184.963,23.044
  rectangle net +5V: 148.438,14.402 155.702,15.748
  rectangle net 28VIN: 13.081,10.795 27.686,13.208
  region net RPD: 225.933,7.747 223.155,7.747 223.155,6.747 225.933,6.747
  region net NetC58_1: 231.76,7.747 229.108,7.747 229.108,6.747 231.76,6.747
  region net NetC58_2: 231.394,16.383 231.394,11.832 232.394,11.832 232.394,16.383
  region net NetC49_2: 208.92,16.681 208.92,11.43 209.92,11.43 209.92,16.681
  region net NetC49_1: 209.789,7.747 207.01,7.747 207.01,6.747 209.789,6.747
  region net OPD: 203.692,7.747 200.914,7.747 200.914,6.747 203.692,6.747
  region net NetC49_1: 209.931,6.731 209.931,9.779 208.931,9.779 208.931,6.731
  region net OPD: 202.705,4.623 202.705,7.112 201.705,7.112 201.705,4.623
  rectangle net 28VIN: 35.687,1.651 37.338,5.055
  rectangle net GND: 33.255,4.47 34.544,8.738
  rectangle net GND: 95.098,20.345 95.468,21.708
  rectangle net GND: 148.946,12.37 152.756,13.005
  rectangle net 3.3VCC1: 111.373,11.811 113.665,12.564
  rectangle net 3.3VCC: 128.473,12.675 129.388,15.977
  rectangle net 3.3VCC: 128.473,15.519 131.135,16.459
  rectangle net +5V: 152.241,5.384 154.13,9.999
  rectangle net +5V: 154.13,5.385 155.702,9.474
  rectangle net +5V: 153.975,8.865 155.702,15.596
  rectangle net 3.3VCC1: 156.845,7.722 158.115,11.157
  rectangle net NetC68_2: 34.544,22.606 54.61,27.559
  rectangle net 28VIN: 212.014,32.436 213.512,33.223
  rectangle net NetC68_2: 151.003,21.844 154.343,24.181
  rectangle net 28VIN: 8.865,5.994 17.729,39.161
  rectangle net GND: 233.13,30.15 234.213,33.128
  rectangle net +5V: 169.037,1.016 169.926,5.461
  region net +5V: 169.405,4.94 169.926,5.461 168.976,6.411 168.455,5.89
  rectangle net GND: 237.719,29.591 239.612,33.147
  rectangle net GND: 172.974,29.972 173.736,32.969
  rectangle net VGS4: 231.394,33.96 234.061,38.862
  rectangle net GND14: 197.866,33.909 200.533,38.811
  rectangle net 28VOUT3: 154.68,32.581 161.011,38.855
  rectangle net 28VOUT3: 154.68,30.937 157.099,32.581
  rectangle net VGS3: 166.624,33.909 169.291,38.811
  rectangle net GND13: 132.588,33.909 135.255,38.811
  region net 28VIN: 152.222,32.43 152.222,39.161 147.218,39.161 147.218,32.43
  rectangle net 28VIN: 149.174,29.642 151.486,33.111
  rectangle net 28VOUT2: 88.894,30.937 91.313,32.581
  rectangle net 28VOUT2: 88.894,32.581 95.225,38.855
  rectangle net 28VIN: 83.261,29.642 85.141,33.111
  region net 28VIN: 86.309,32.43 86.309,39.161 81.305,39.161 81.305,32.43
  rectangle net 28VIN: 81.305,30.277 85.217,33.223
  rectangle net GND12: 67.818,33.858 70.485,38.76
  rectangle net VGS2: 101.473,33.909 104.14,38.811
  rectangle net 28VIN: 17.348,32.436 18.847,33.223
  region net 28VIN: 22.174,32.43 22.174,39.161 17.17,39.161 17.17,32.43
  rectangle net 28VIN: 19.456,29.642 21.438,33.111
  rectangle net 28VOUT1: 24.765,32.581 30.709,38.855
  rectangle net 28VOUT1: 25.375,30.937 26.899,33.782
  rectangle net VGS1: 36.576,34.036 39.243,38.938
  rectangle net GND11: 2.184,36.703 6.253,39.116
  region net 28VIN: 18.061,17.807 21.717,21.463 16.319,26.861 12.664,23.205
  rectangle net NetD1_2: 39.737,4.967 43.18,15.24
  rectangle net 28VIN: 35.687,1.651 37.846,5.055
  region net NetD1_2: 39.737,4.967 41.056,6.287 40.054,7.288 38.735,5.969
  rectangle net NetD1_2: 37.973,11.557 43.18,15.621
  rectangle net +5V_1: 41.351,34.036 43.891,38.938
  rectangle net NetC18_2: 173.051,20.532 177.673,23.495
  rectangle net NetC18_2: 175.463,19.914 177.673,24.359
  rectangle net +5V_2: 106.172,33.909 108.712,38.811
  rectangle net +5V_3: 171.196,33.909 173.736,38.811
  rectangle net +5V_4: 235.966,33.96 238.506,38.862
  rectangle net GND11: 5.131,30.69 6.253,38.76
  pour cut-out: 113.811,12.785 113.811,14.09 113.665,14.236 111.418,14.236 111.021,13.839 111.021,13.058 111.294,12.785
  pour cut-out: 6.026,3.048 6.026,41.738 6.629,42.342 19.152,42.342 19.787,41.707 19.787,26.368 19.771,26.352 24.308,21.815 24.308,17.932 24.765,17.475 24.765,-2.896 22.098,-5.563 6.528,-5.563 6.528,2.546
  pour cut-out: 24.765,17.475 24.765,22.098 19.66,27.203 18.237,27.203 17.882,26.848 17.882,24.359
  pour cut-out: 18.821,30.683 241.427,30.683 241.579,30.836 241.579,39.954 240.843,40.691 18.11,40.691 17.628,40.208 17.628,31.877
  region net NetC59_2: 226.179,16.285 226.179,15.929 228.084,15.929 228.769,15.599 229.898,15.599 229.898,16.599 228.769,16.599 228.058,16.285
  region net NetC50_2: 204.008,16.449 204.008,16.093 205.913,16.093 206.599,15.763 207.727,15.763 207.727,16.763 206.599,16.763 205.888,16.449
  pour cut-out: 115.056,21.355 111.167,21.355 111.02,21.207 111.02,13.841 111.021,13.839 115.209,13.839 115.338,13.968 115.338,21.073
  pour cut-out: 70.405,15.352 70.405,22.541 70.329,22.617 76.552,22.617 76.552,9.817 70.329,9.817 70.329,22.617
  pour cut-out: 136.032,22.733 140.767,22.733 140.767,26.213 144.069,26.213 144.069,25.527 144.232,25.527 144.232,19.304 136.032,19.304
  pour cut-out: 71.196,25.794 77.953,25.794 77.953,22.77 70.841,22.77 70.841,25.793 71.196,25.793
  pour cut-out: 66.192,23.012 66.192,25.806 65.049,25.806 65.049,23.012
  pour cut-out: 227.051,40.665 227.051,31.42 226.746,31.115 221.844,31.115 221.615,31.344 221.615,40.411 221.869,40.665
  pour cut-out: 53.975,20.413 55.719,20.413 56.642,21.336 56.642,28.194 56.261,28.575 54.991,28.575 53.721,27.305 53.975,27.051
  pour cut-out: 155.494,24.487 154.408,24.487 154.305,24.384 154.305,21.717 154.535,21.487 156.032,21.487 156.163,21.618 156.163,23.818
  pour cut-out: 221.893,0.865 222.123,0.635 224.536,0.635 224.964,1.063 224.964,5.325 233.22,5.325 233.402,5.507 233.402,16.836 232.83,17.408 228.101,17.408 227.711,17.018 227.711,15.113 227.845,14.979 230.369,14.979 230.369,8.375 221.986,8.375 221.893,8.282
  pour cut-out: 230.369,8.375 230.369,8.883 221.876,8.883 221.869,8.89 221.361,8.89 221.361,0.889 221.869,0.381 222.25,0.762 225.438,0.762 225.438,4.94 225.425,4.953 233.553,4.953 233.68,5.08 233.68,8.128 233.426,8.382 233.419,8.375
  pour cut-out: 205.92,17.706 205.74,17.526 205.74,15.113 205.994,14.859 207.788,14.859 207.895,14.752 207.895,9.394 207.772,9.271 199.009,9.271 198.882,9.144 198.882,0.889 199.263,0.508 204.47,0.508 204.724,0.762 204.724,4.826 204.851,4.953 210.693,4.953 210.956,5.216 210.956,17.094 210.344,17.706
  pour cut-out: 233.68,8.128 233.68,8.636 233.172,8.636 233.172,8.382 233.426,8.128
  pour cut-out: 4.318,35.433 -0.889,35.433 -1.143,35.687 -1.143,36.322 -0.762,36.703 3.937,36.703 4.318,36.322
S2:
  rectangle net 28VIN: 8.865,4.005 21.717,21.463
  rectangle net 28VIN: 8.865,32.385 218.211,39.161
  pour cut-out: 24.765,21.358 21.866,24.257 6.35,24.257 6.026,23.933 6.026,-3.105 7.493,-4.572 21.971,-4.572 24.765,-1.778
  pour cut-out: 70.405,15.352 70.405,22.541 70.329,22.617 76.552,22.617 76.552,9.817 70.329,9.817 70.329,22.617
S3:
  rectangle net 28VIN: 8.89,4.005 21.717,21.463
  rectangle net 28VIN: 8.865,32.41 218.084,39.161
  pour cut-out: 24.765,21.358 21.866,24.257 6.35,24.257 6.026,23.933 6.026,-3.105 7.493,-4.572 21.971,-4.572 24.765,-1.778
  pour cut-out: 24.765,21.358 24.308,21.815 23.466,21.815 23.292,21.641 23.292,17.348 23.546,17.094 24.689,17.094 24.765,17.17
  pour cut-out: 70.405,15.352 70.405,22.541 70.329,22.617 76.552,22.617 76.552,9.817 70.329,9.817 70.329,22.617
Bottom Layer:
  region net 28VIN: 16.91,30.88 19.251,33.221 18.353,34.12 16.012,31.778
  rectangle net 28VIN: 8.865,4.005 21.717,21.463
  rectangle net 28VIN: 8.865,32.41 218.237,39.161
  rectangle net 28VIN: 8.865,16.891 17.729,39.161
  region net 28VIN: 18.489,18.235 21.717,21.463 16.32,26.86 13.091,23.632
  pour cut-out: 24.765,21.358 24.308,21.815 23.212,21.815 22.835,21.438 23.139,21.133 23.139,16.129 23.952,16.129 24.765,16.942
  pour cut-out: 6.026,3.048 6.026,41.738 6.629,42.342 19.152,42.342 19.787,41.707 19.787,26.368 19.771,26.352 24.308,21.815 24.308,17.932 24.765,17.475 24.765,-2.896 22.098,-5.563 6.528,-5.563 6.528,2.546
  pour cut-out: 70.405,15.352 70.405,22.541 70.329,22.617 76.552,22.617 76.552,9.817 70.329,9.817 70.329,22.617

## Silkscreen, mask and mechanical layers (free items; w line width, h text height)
Top Overlay:
  lines w0.254: 191.999,0 191.999,24.377 240,24.377 ; 196.113,22.093 213.586,22.093 213.59,0 ; 196.114,22.123 196.118,0 ; 217.698,0 217.698,22.098 ; 217.698,22.156 240,22.156
  text "GND" at 7,36 h1.5 r90
  text "GND" at 72.002,35.712 h1.5 r90
  text "Vgs" at 40.386,35.636 h1.5 r90
  text "Ptt" at 44.958,35.636 h1.5 r90
  text "GND" at 136.779,35.56 h1.5 r90
  text "GND" at 202.184,35.56 h1.5 r90
  text "Vds" at 227.076,35.56 h1.5 r90
  text "Vgs" at 235.204,35.56 h1.5 r90
  text "Ptt" at 239.649,35.56 h1.5 r90
  text "Vds" at 32.766,35.509 h1.5 r90
  text "Vds" at 97.282,35.509 h1.5 r90
  text "Vgs" at 105.41,35.509 h1.5 r90
  text "Ptt" at 109.855,35.509 h1.5 r90
  text "Vds" at 162.306,35.509 h1.5 r90
  text "Vgs" at 170.434,35.509 h1.5 r90
  text "Ptt" at 174.879,35.509 h1.5 r90
  text "WS7.820.291.V07" at 187.325,27.051 h2
  text "1" at 132.715,9.398 h1
  text "2" at 135.001,9.398 h1
  text "3" at 137.541,9.398 h1
  text "4" at 139.954,9.398 h1
  text "5" at 142.621,9.398 h1
  text "6" at 145.288,9.398 h1
  text "POWER IN" at 8.128,3.937 h1.27 r90
  text "OPD" at 198.247,2.413 h1.52 r90
  text "RPD" at 219.964,2.413 h1.52 r90
  text "GND" at 116.713,1.651 h0.8 r90
  text "3.3V" at 111.506,1.143 h0.8 r90
  text "Temp" at 114.109,1.143 h0.8 r90
Top Solder:
  rectangle: 223.155,6.747 225.933,7.747
  rectangle: 208.92,11.43 209.92,16.681
  rectangle: 208.931,6.731 209.931,9.779
  rectangle: 207.01,6.747 209.789,7.747
  rectangle: 200.914,6.747 203.692,7.747
  rectangle: 229.108,6.747 231.76,7.747
  rectangle: 231.394,6.477 232.394,9.906
  rectangle: 231.394,11.832 232.394,16.383
  rectangle: 39.893,0.889 43.561,3.81
  rectangle: 15.596,10.084 21.895,12.979
  rectangle: 219.298,32.581 225.628,38.855
  rectangle: 8.89,4.064 17.475,38.938
  rectangle: 201.705,4.623 202.705,6.8
  rectangle: 222.939,4.63 223.939,6.807
  rectangle: 128.473,15.519 131.135,16.459
  rectangle: 130.194,12.37 132.055,14.351
  rectangle: 231.394,35.179 234.061,38.862
  rectangle: 197.866,35.179 200.533,38.811
  rectangle: 154.68,32.581 161.011,38.855
  rectangle: 166.624,35.128 169.291,38.811
  rectangle: 132.588,35.128 135.255,38.811
  rectangle: 88.894,32.581 95.225,38.855
  rectangle: 67.818,35.077 70.485,38.76
  rectangle: 101.473,35.128 104.14,38.811
  rectangle: 17.17,32.416 19.126,38.938
  rectangle: 24.378,32.581 30.709,38.855
  rectangle: 36.576,35.255 39.243,38.938
  rectangle: 2.184,36.703 5.563,39.116
  rectangle: 41.351,35.255 43.891,38.938
  rectangle: 106.172,35.128 108.712,38.811
  rectangle: 171.196,35.128 173.736,38.811
  rectangle: 235.966,35.179 238.506,38.862
  region: 226.179,16.285 226.179,15.929 228.084,15.929 228.769,15.599 229.898,15.599 229.898,16.599 228.769,16.599 228.058,16.285
  region: 204.008,16.449 204.008,16.093 205.913,16.093 206.599,15.763 207.727,15.763 207.727,16.763 206.599,16.763 205.888,16.449
Bottom Solder:
  rectangle: 26.162,0.254 49.022,25.781
  region: 100.767,14.097 100.767,23.241 94.107,23.241 94.107,14.097
  region: 103.378,14.097 103.378,21.082 100.767,21.082 100.767,14.097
